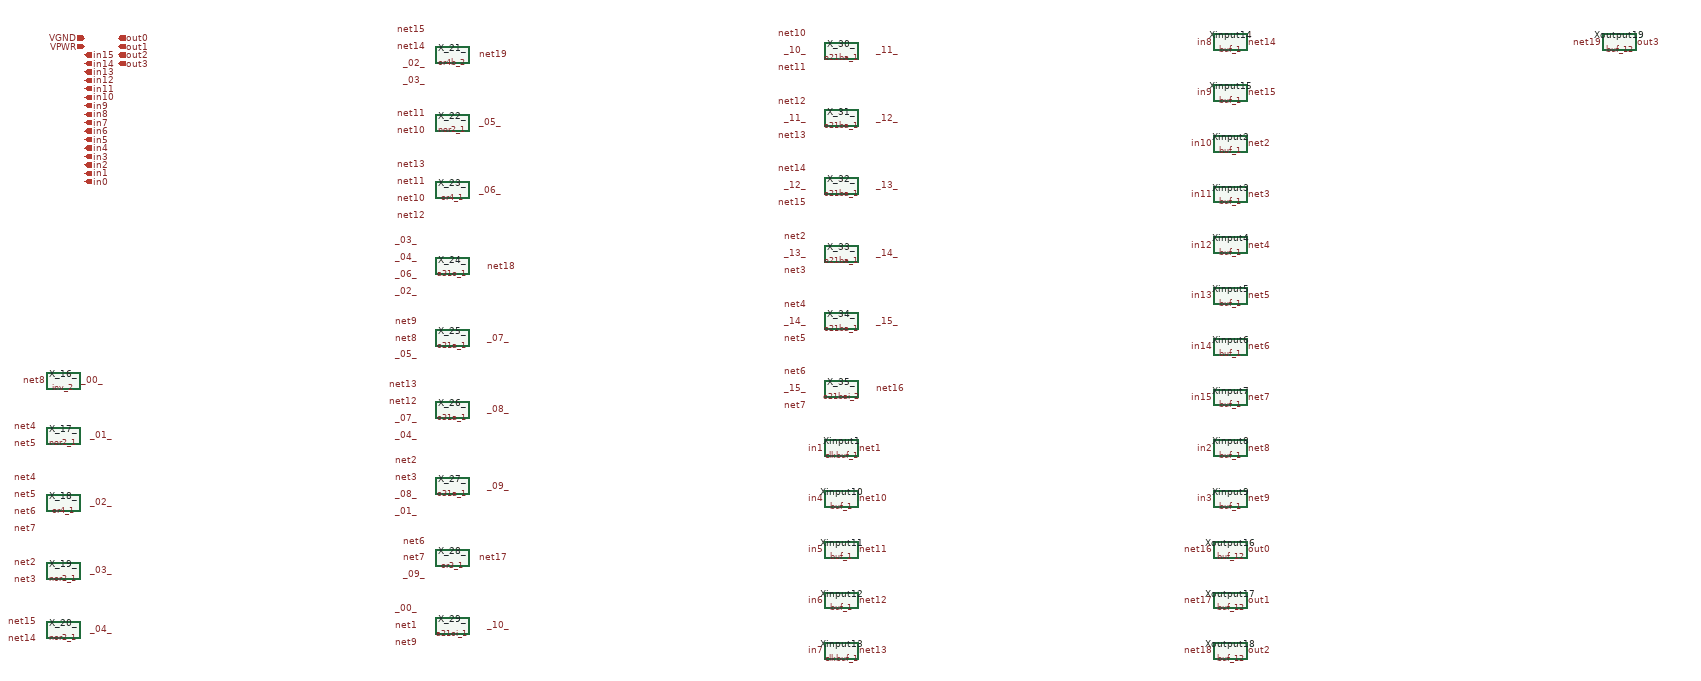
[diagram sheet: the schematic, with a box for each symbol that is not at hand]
v {xschem version=3.4.4 file_version=1.2
}
G {}
K {}
V {}
S {}
E {}
C {devices/ipin.sym} 190 20 0 0 {name=p118 lab=VGND }
C {devices/ipin.sym} 190 40 0 0 {name=p119 lab=VPWR }
C {devices/ipin.sym} 190 360 2 1 {name=p120 lab=in0 }
C {devices/ipin.sym} 190 340 2 1 {name=p121 lab=in1 }
C {devices/ipin.sym} 190 160 2 1 {name=p122 lab=in10 }
C {devices/ipin.sym} 190 140 2 1 {name=p123 lab=in11 }
C {devices/ipin.sym} 190 120 2 1 {name=p124 lab=in12 }
C {devices/ipin.sym} 190 100 2 1 {name=p125 lab=in13 }
C {devices/ipin.sym} 190 80 2 1 {name=p126 lab=in14 }
C {devices/ipin.sym} 190 60 2 1 {name=p127 lab=in15 }
C {devices/ipin.sym} 190 320 2 1 {name=p128 lab=in2 }
C {devices/ipin.sym} 190 300 2 1 {name=p129 lab=in3 }
C {devices/ipin.sym} 190 280 2 1 {name=p130 lab=in4 }
C {devices/ipin.sym} 190 260 2 1 {name=p131 lab=in5 }
C {devices/ipin.sym} 190 240 2 1 {name=p132 lab=in6 }
C {devices/ipin.sym} 190 220 2 1 {name=p133 lab=in7 }
C {devices/ipin.sym} 190 200 2 1 {name=p134 lab=in8 }
C {devices/ipin.sym} 190 180 2 1 {name=p135 lab=in9 }
C {devices/opin.sym} 270 20 0 0 {name=p136 lab=out0 }
C {devices/opin.sym} 270 40 0 0 {name=p137 lab=out1 }
C {devices/opin.sym} 270 60 0 0 {name=p138 lab=out2 }
C {devices/opin.sym} 270 80 0 0 {name=p139 lab=out3 }
C {devices/lab_pin.sym} 100 830 0 0 {name=p0 lab=net8 }
C {devices/lab_pin.sym} 180 830 0 1 {name=p1 lab=_00_ }
C {sky130_stdcells/inv_2.sym} 140 830 0 0 {name=X_16_ VGND=VGND VNB=VGND VPB=VPWR VPWR=VPWR }
C {devices/lab_pin.sym} 80 940 0 0 {name=p2 lab=net4 }
C {devices/lab_pin.sym} 80 980 0 0 {name=p3 lab=net5 }
C {devices/lab_pin.sym} 200 960 0 1 {name=p4 lab=_01_ }
C {sky130_stdcells/nor2_1.sym} 140 960 0 0 {name=X_17_ VGND=VGND VNB=VGND VPB=VPWR VPWR=VPWR }
C {devices/lab_pin.sym} 80 1060 0 0 {name=p5 lab=net4 }
C {devices/lab_pin.sym} 80 1100 0 0 {name=p6 lab=net5 }
C {devices/lab_pin.sym} 80 1140 0 0 {name=p7 lab=net6 }
C {devices/lab_pin.sym} 80 1180 0 0 {name=p8 lab=net7 }
C {devices/lab_pin.sym} 200 1120 0 1 {name=p9 lab=_02_ }
C {sky130_stdcells/or4_1.sym} 140 1120 0 0 {name=X_18_ VGND=VGND VNB=VGND VPB=VPWR VPWR=VPWR }
C {devices/lab_pin.sym} 80 1260 0 0 {name=p10 lab=net2 }
C {devices/lab_pin.sym} 80 1300 0 0 {name=p11 lab=net3 }
C {devices/lab_pin.sym} 200 1280 0 1 {name=p12 lab=_03_ }
C {sky130_stdcells/nor2_1.sym} 140 1280 0 0 {name=X_19_ VGND=VGND VNB=VGND VPB=VPWR VPWR=VPWR }
C {devices/lab_pin.sym} 80 1400 0 0 {name=p13 lab=net15 }
C {devices/lab_pin.sym} 80 1440 0 0 {name=p14 lab=net14 }
C {devices/lab_pin.sym} 200 1420 0 1 {name=p15 lab=_04_ }
C {sky130_stdcells/nor2_1.sym} 140 1420 0 0 {name=X_20_ VGND=VGND VNB=VGND VPB=VPWR VPWR=VPWR }
C {devices/lab_pin.sym} 1000 0 0 0 {name=p16 lab=net15 }
C {devices/lab_pin.sym} 1000 40 0 0 {name=p17 lab=net14 }
C {devices/lab_pin.sym} 1000 80 0 0 {name=p18 lab=_02_ }
C {devices/lab_pin.sym} 1000 120 0 0 {name=p19 lab=_03_ }
C {devices/lab_pin.sym} 1120 60 0 1 {name=p20 lab=net19 }
C {sky130_stdcells/or4b_2.sym} 1060 60 0 0 {name=X_21_ VGND=VGND VNB=VGND VPB=VPWR VPWR=VPWR }
C {devices/lab_pin.sym} 1000 200 0 0 {name=p21 lab=net11 }
C {devices/lab_pin.sym} 1000 240 0 0 {name=p22 lab=net10 }
C {devices/lab_pin.sym} 1120 220 0 1 {name=p23 lab=_05_ }
C {sky130_stdcells/nor2_1.sym} 1060 220 0 0 {name=X_22_ VGND=VGND VNB=VGND VPB=VPWR VPWR=VPWR }
C {devices/lab_pin.sym} 1000 320 0 0 {name=p24 lab=net13 }
C {devices/lab_pin.sym} 1000 360 0 0 {name=p25 lab=net11 }
C {devices/lab_pin.sym} 1000 400 0 0 {name=p26 lab=net10 }
C {devices/lab_pin.sym} 1000 440 0 0 {name=p27 lab=net12 }
C {devices/lab_pin.sym} 1120 380 0 1 {name=p28 lab=_06_ }
C {sky130_stdcells/or4_1.sym} 1060 380 0 0 {name=X_23_ VGND=VGND VNB=VGND VPB=VPWR VPWR=VPWR }
C {devices/lab_pin.sym} 980 500 0 0 {name=p29 lab=_03_ }
C {devices/lab_pin.sym} 980 540 0 0 {name=p30 lab=_04_ }
C {devices/lab_pin.sym} 980 580 0 0 {name=p31 lab=_06_ }
C {devices/lab_pin.sym} 980 620 0 0 {name=p32 lab=_02_ }
C {devices/lab_pin.sym} 1140 560 0 1 {name=p33 lab=net18 }
C {sky130_stdcells/a31o_1.sym} 1060 560 0 0 {name=X_24_ VGND=VGND VNB=VGND VPB=VPWR VPWR=VPWR }
C {devices/lab_pin.sym} 980 690 0 0 {name=p34 lab=net9 }
C {devices/lab_pin.sym} 980 730 0 0 {name=p35 lab=net8 }
C {devices/lab_pin.sym} 980 770 0 0 {name=p36 lab=_05_ }
C {devices/lab_pin.sym} 1140 730 0 1 {name=p37 lab=_07_ }
C {sky130_stdcells/o21a_1.sym} 1060 730 0 0 {name=X_25_ VGND=VGND VNB=VGND VPB=VPWR VPWR=VPWR }
C {devices/lab_pin.sym} 980 840 0 0 {name=p38 lab=net13 }
C {devices/lab_pin.sym} 980 880 0 0 {name=p39 lab=net12 }
C {devices/lab_pin.sym} 980 920 0 0 {name=p40 lab=_07_ }
C {devices/lab_pin.sym} 980 960 0 0 {name=p41 lab=_04_ }
C {devices/lab_pin.sym} 1140 900 0 1 {name=p42 lab=_08_ }
C {sky130_stdcells/o31a_1.sym} 1060 900 0 0 {name=X_26_ VGND=VGND VNB=VGND VPB=VPWR VPWR=VPWR }
C {devices/lab_pin.sym} 980 1020 0 0 {name=p43 lab=net2 }
C {devices/lab_pin.sym} 980 1060 0 0 {name=p44 lab=net3 }
C {devices/lab_pin.sym} 980 1100 0 0 {name=p45 lab=_08_ }
C {devices/lab_pin.sym} 980 1140 0 0 {name=p46 lab=_01_ }
C {devices/lab_pin.sym} 1140 1080 0 1 {name=p47 lab=_09_ }
C {sky130_stdcells/o31a_1.sym} 1060 1080 0 0 {name=X_27_ VGND=VGND VNB=VGND VPB=VPWR VPWR=VPWR }
C {devices/lab_pin.sym} 1000 1210 0 0 {name=p48 lab=net6 }
C {devices/lab_pin.sym} 1000 1250 0 0 {name=p49 lab=net7 }
C {devices/lab_pin.sym} 1000 1290 0 0 {name=p50 lab=_09_ }
C {devices/lab_pin.sym} 1120 1250 0 1 {name=p51 lab=net17 }
C {sky130_stdcells/or3_1.sym} 1060 1250 0 0 {name=X_28_ VGND=VGND VNB=VGND VPB=VPWR VPWR=VPWR }
C {devices/lab_pin.sym} 980 1370 0 0 {name=p52 lab=_00_ }
C {devices/lab_pin.sym} 980 1410 0 0 {name=p53 lab=net1 }
C {devices/lab_pin.sym} 980 1450 0 0 {name=p54 lab=net9 }
C {devices/lab_pin.sym} 1140 1410 0 1 {name=p55 lab=_10_ }
C {sky130_stdcells/a21oi_1.sym} 1060 1410 0 0 {name=X_29_ VGND=VGND VNB=VGND VPB=VPWR VPWR=VPWR }
C {devices/lab_pin.sym} 1900 10 0 0 {name=p56 lab=net10 }
C {devices/lab_pin.sym} 1900 50 0 0 {name=p57 lab=_10_ }
C {devices/lab_pin.sym} 1900 90 0 0 {name=p58 lab=net11 }
C {devices/lab_pin.sym} 2060 50 0 1 {name=p59 lab=_11_ }
C {sky130_stdcells/o21ba_1.sym} 1980 50 0 0 {name=X_30_ VGND=VGND VNB=VGND VPB=VPWR VPWR=VPWR }
C {devices/lab_pin.sym} 1900 170 0 0 {name=p60 lab=net12 }
C {devices/lab_pin.sym} 1900 210 0 0 {name=p61 lab=_11_ }
C {devices/lab_pin.sym} 1900 250 0 0 {name=p62 lab=net13 }
C {devices/lab_pin.sym} 2060 210 0 1 {name=p63 lab=_12_ }
C {sky130_stdcells/o21ba_1.sym} 1980 210 0 0 {name=X_31_ VGND=VGND VNB=VGND VPB=VPWR VPWR=VPWR }
C {devices/lab_pin.sym} 1900 330 0 0 {name=p64 lab=net14 }
C {devices/lab_pin.sym} 1900 370 0 0 {name=p65 lab=_12_ }
C {devices/lab_pin.sym} 1900 410 0 0 {name=p66 lab=net15 }
C {devices/lab_pin.sym} 2060 370 0 1 {name=p67 lab=_13_ }
C {sky130_stdcells/o21ba_1.sym} 1980 370 0 0 {name=X_32_ VGND=VGND VNB=VGND VPB=VPWR VPWR=VPWR }
C {devices/lab_pin.sym} 1900 490 0 0 {name=p68 lab=net2 }
C {devices/lab_pin.sym} 1900 530 0 0 {name=p69 lab=_13_ }
C {devices/lab_pin.sym} 1900 570 0 0 {name=p70 lab=net3 }
C {devices/lab_pin.sym} 2060 530 0 1 {name=p71 lab=_14_ }
C {sky130_stdcells/o21ba_1.sym} 1980 530 0 0 {name=X_33_ VGND=VGND VNB=VGND VPB=VPWR VPWR=VPWR }
C {devices/lab_pin.sym} 1900 650 0 0 {name=p72 lab=net4 }
C {devices/lab_pin.sym} 1900 690 0 0 {name=p73 lab=_14_ }
C {devices/lab_pin.sym} 1900 730 0 0 {name=p74 lab=net5 }
C {devices/lab_pin.sym} 2060 690 0 1 {name=p75 lab=_15_ }
C {sky130_stdcells/o21ba_1.sym} 1980 690 0 0 {name=X_34_ VGND=VGND VNB=VGND VPB=VPWR VPWR=VPWR }
C {devices/lab_pin.sym} 1900 810 0 0 {name=p76 lab=net6 }
C {devices/lab_pin.sym} 1900 850 0 0 {name=p77 lab=_15_ }
C {devices/lab_pin.sym} 1900 890 0 0 {name=p78 lab=net7 }
C {devices/lab_pin.sym} 2060 850 0 1 {name=p79 lab=net16 }
C {sky130_stdcells/o21bai_2.sym} 1980 850 0 0 {name=X_35_ VGND=VGND VNB=VGND VPB=VPWR VPWR=VPWR }
C {devices/lab_pin.sym} 1940 990 0 0 {name=p80 lab=in1 }
C {devices/lab_pin.sym} 2020 990 0 1 {name=p81 lab=net1 }
C {sky130_stdcells/clkbuf_1.sym} 1980 990 0 0 {name=Xinput1 VGND=VGND VNB=VGND VPB=VPWR VPWR=VPWR }
C {devices/lab_pin.sym} 1940 1110 0 0 {name=p82 lab=in4 }
C {devices/lab_pin.sym} 2020 1110 0 1 {name=p83 lab=net10 }
C {sky130_stdcells/buf_1.sym} 1980 1110 0 0 {name=Xinput10 VGND=VGND VNB=VGND VPB=VPWR VPWR=VPWR }
C {devices/lab_pin.sym} 1940 1230 0 0 {name=p84 lab=in5 }
C {devices/lab_pin.sym} 2020 1230 0 1 {name=p85 lab=net11 }
C {sky130_stdcells/buf_1.sym} 1980 1230 0 0 {name=Xinput11 VGND=VGND VNB=VGND VPB=VPWR VPWR=VPWR }
C {devices/lab_pin.sym} 1940 1350 0 0 {name=p86 lab=in6 }
C {devices/lab_pin.sym} 2020 1350 0 1 {name=p87 lab=net12 }
C {sky130_stdcells/buf_1.sym} 1980 1350 0 0 {name=Xinput12 VGND=VGND VNB=VGND VPB=VPWR VPWR=VPWR }
C {devices/lab_pin.sym} 1940 1470 0 0 {name=p88 lab=in7 }
C {devices/lab_pin.sym} 2020 1470 0 1 {name=p89 lab=net13 }
C {sky130_stdcells/clkbuf_1.sym} 1980 1470 0 0 {name=Xinput13 VGND=VGND VNB=VGND VPB=VPWR VPWR=VPWR }
C {devices/lab_pin.sym} 2860 30 0 0 {name=p90 lab=in8 }
C {devices/lab_pin.sym} 2940 30 0 1 {name=p91 lab=net14 }
C {sky130_stdcells/buf_1.sym} 2900 30 0 0 {name=Xinput14 VGND=VGND VNB=VGND VPB=VPWR VPWR=VPWR }
C {devices/lab_pin.sym} 2860 150 0 0 {name=p92 lab=in9 }
C {devices/lab_pin.sym} 2940 150 0 1 {name=p93 lab=net15 }
C {sky130_stdcells/buf_1.sym} 2900 150 0 0 {name=Xinput15 VGND=VGND VNB=VGND VPB=VPWR VPWR=VPWR }
C {devices/lab_pin.sym} 2860 270 0 0 {name=p94 lab=in10 }
C {devices/lab_pin.sym} 2940 270 0 1 {name=p95 lab=net2 }
C {sky130_stdcells/buf_1.sym} 2900 270 0 0 {name=Xinput2 VGND=VGND VNB=VGND VPB=VPWR VPWR=VPWR }
C {devices/lab_pin.sym} 2860 390 0 0 {name=p96 lab=in11 }
C {devices/lab_pin.sym} 2940 390 0 1 {name=p97 lab=net3 }
C {sky130_stdcells/buf_1.sym} 2900 390 0 0 {name=Xinput3 VGND=VGND VNB=VGND VPB=VPWR VPWR=VPWR }
C {devices/lab_pin.sym} 2860 510 0 0 {name=p98 lab=in12 }
C {devices/lab_pin.sym} 2940 510 0 1 {name=p99 lab=net4 }
C {sky130_stdcells/buf_1.sym} 2900 510 0 0 {name=Xinput4 VGND=VGND VNB=VGND VPB=VPWR VPWR=VPWR }
C {devices/lab_pin.sym} 2860 630 0 0 {name=p100 lab=in13 }
C {devices/lab_pin.sym} 2940 630 0 1 {name=p101 lab=net5 }
C {sky130_stdcells/buf_1.sym} 2900 630 0 0 {name=Xinput5 VGND=VGND VNB=VGND VPB=VPWR VPWR=VPWR }
C {devices/lab_pin.sym} 2860 750 0 0 {name=p102 lab=in14 }
C {devices/lab_pin.sym} 2940 750 0 1 {name=p103 lab=net6 }
C {sky130_stdcells/buf_1.sym} 2900 750 0 0 {name=Xinput6 VGND=VGND VNB=VGND VPB=VPWR VPWR=VPWR }
C {devices/lab_pin.sym} 2860 870 0 0 {name=p104 lab=in15 }
C {devices/lab_pin.sym} 2940 870 0 1 {name=p105 lab=net7 }
C {sky130_stdcells/buf_1.sym} 2900 870 0 0 {name=Xinput7 VGND=VGND VNB=VGND VPB=VPWR VPWR=VPWR }
C {devices/lab_pin.sym} 2860 990 0 0 {name=p106 lab=in2 }
C {devices/lab_pin.sym} 2940 990 0 1 {name=p107 lab=net8 }
C {sky130_stdcells/buf_1.sym} 2900 990 0 0 {name=Xinput8 VGND=VGND VNB=VGND VPB=VPWR VPWR=VPWR }
C {devices/lab_pin.sym} 2860 1110 0 0 {name=p108 lab=in3 }
C {devices/lab_pin.sym} 2940 1110 0 1 {name=p109 lab=net9 }
C {sky130_stdcells/buf_1.sym} 2900 1110 0 0 {name=Xinput9 VGND=VGND VNB=VGND VPB=VPWR VPWR=VPWR }
C {devices/lab_pin.sym} 2860 1230 0 0 {name=p110 lab=net16 }
C {devices/lab_pin.sym} 2940 1230 0 1 {name=p111 lab=out0 }
C {sky130_stdcells/buf_12.sym} 2900 1230 0 0 {name=Xoutput16 VGND=VGND VNB=VGND VPB=VPWR VPWR=VPWR }
C {devices/lab_pin.sym} 2860 1350 0 0 {name=p112 lab=net17 }
C {devices/lab_pin.sym} 2940 1350 0 1 {name=p113 lab=out1 }
C {sky130_stdcells/buf_12.sym} 2900 1350 0 0 {name=Xoutput17 VGND=VGND VNB=VGND VPB=VPWR VPWR=VPWR }
C {devices/lab_pin.sym} 2860 1470 0 0 {name=p114 lab=net18 }
C {devices/lab_pin.sym} 2940 1470 0 1 {name=p115 lab=out2 }
C {sky130_stdcells/buf_12.sym} 2900 1470 0 0 {name=Xoutput18 VGND=VGND VNB=VGND VPB=VPWR VPWR=VPWR }
C {devices/lab_pin.sym} 3780 30 0 0 {name=p116 lab=net19 }
C {devices/lab_pin.sym} 3860 30 0 1 {name=p117 lab=out3 }
C {sky130_stdcells/buf_12.sym} 3820 30 0 0 {name=Xoutput19 VGND=VGND VNB=VGND VPB=VPWR VPWR=VPWR }
